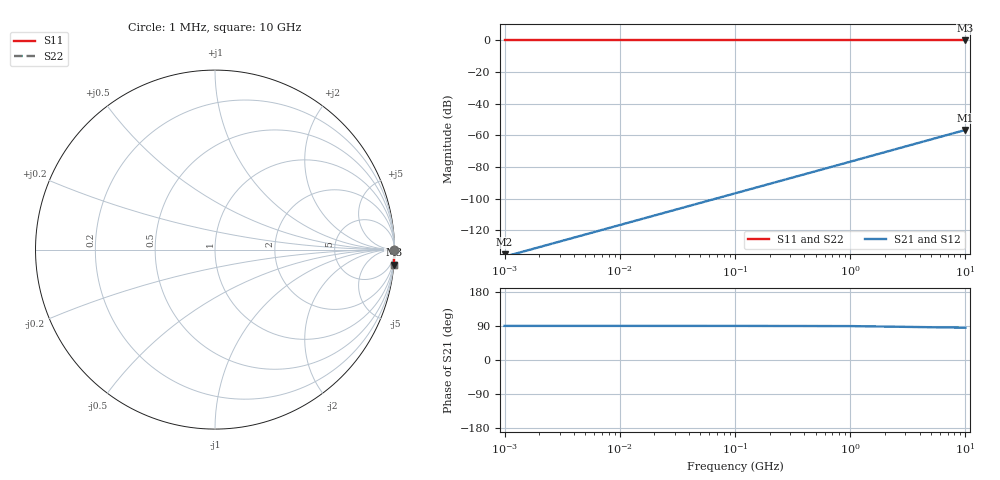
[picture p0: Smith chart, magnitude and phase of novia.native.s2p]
! Sonnet Data File
! From: em Version : 18.53-Lite
! From Project: novia
! Data is NOT De-embedded
! Data File Written: 10/12/2026 10:25:33
!< HDATE 10/12/2026 10:25:33
!< MDATE 10/12/2026 10:25:33
# GHZ S RI R 50.00000
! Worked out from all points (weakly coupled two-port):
!   5 points, 1 MHz to 10 GHz, reference 50 ohm
!   highest |S21| = -56.56 dB at 10 GHz (marker M1); lowest = -136.6 dB at 1 MHz (marker M2)
!   lowest |S11| = 0.0 dB at 10 GHz (marker M3)
!   |S11| at or under -10 dB: nowhere
!   |S22| runs from 0.0 to 0.0 dB; largest |S21 - S12| = 6e-13
0.001  1 -8.39e-06  1.24e-12 1.47e-07  1.24e-12 1.47e-07  1 -8.39e-06
0.01  1 -8.39e-05  1.24e-10 1.47e-06  1.24e-10 1.47e-06  1 -8.39e-05
0.1  1 -0.000839  1.24e-08 1.47e-05  1.24e-08 1.47e-05  1 -0.000839
1  1 -0.00839  1.24e-06 0.000147  1.24e-06 0.000147  1 -0.00839
10  0.9965 -0.084  0.000125 0.00148  0.000125 0.00148  0.9965 -0.084
